VERSION 5.8 ;
BUSBITCHARS "<>" ;
DIVIDERCHAR "/" ;

UNITS
   DATABASE MICRONS 1000 ;
END UNITS

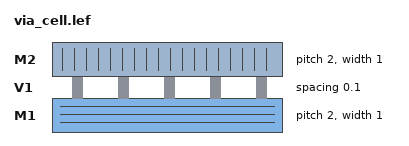
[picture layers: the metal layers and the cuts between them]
LAYER M1
   TYPE ROUTING ;
   WIDTH 1 ;
   PITCH 2 ;
   DIRECTION HORIZONTAL ;
END M1

LAYER V1
   TYPE CUT ;
   SPACING 0.1 ;
END V1

LAYER M2
   TYPE ROUTING ;
   WIDTH 1 ;
   PITCH 2 ;
   DIRECTION VERTICAL ;
END M2

VIA VIA12 DEFAULT
   LAYER M1 ;
      RECT -0.5 -0.5 0.5 0.5 ;
   LAYER V1 ;
      RECT -0.2 -0.2 0.2 0.2 ;
   LAYER M2 ;
      RECT -0.5 -0.5 0.5 0.5 ;
END VIA12

# Pin A: an M1 rect at (1,1)-(3,3)um, plus a VIA12 at (7,7)um.
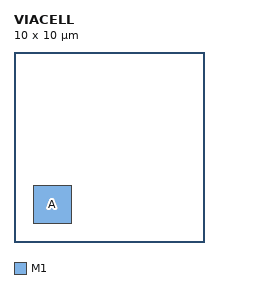
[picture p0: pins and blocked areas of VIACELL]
MACRO VIACELL
   CLASS CORE ;
   SIZE 10 BY 10 ;

   PIN A
      DIRECTION INPUT ;
      PORT
         LAYER M1 ;
         RECT 1 1 3 3 ;
         VIA 7 7 VIA12 ;
      END
   END A
END VIACELL
